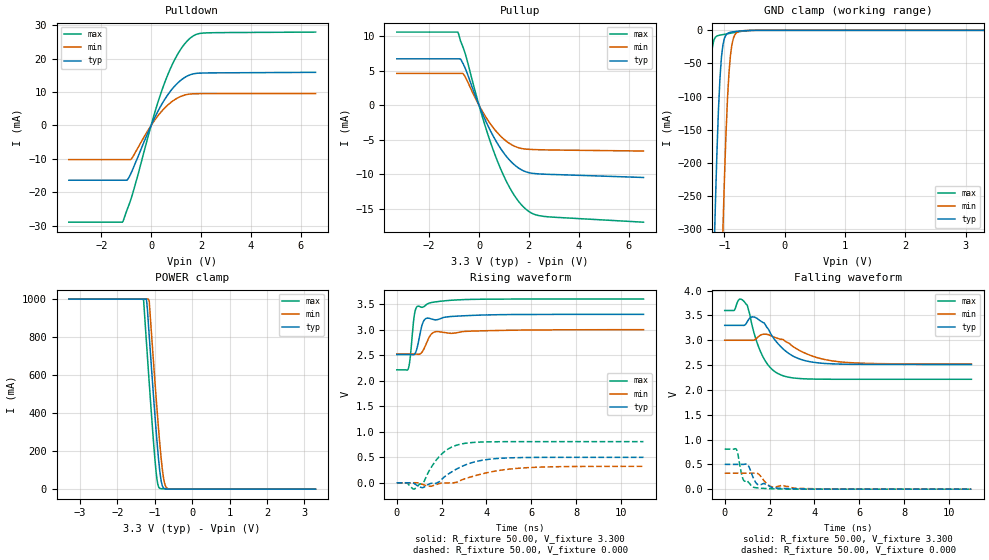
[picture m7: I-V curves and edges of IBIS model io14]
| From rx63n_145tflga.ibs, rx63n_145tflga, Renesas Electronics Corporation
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[Model]   io14
Model_type   I/O
Polarity   Non-Inverting
Enable   Active-High
Vinl  =   0.660V
Vinh  =   2.640V
Vmeas =   1.650V
Cref  =   30.00pF
| variable   typ   min   max
C_comp   4.990pF   4.990pF   4.990pF
| variable   typ   min   max
[Temperature Range]   45.000   105.000   -40.000
| variable   typ   min   max
[Voltage Range]   3.300V   3.000V   3.600V
| variable   typ   min   max
[Pullup Reference]   3.300V   3.000V   3.600V
| variable   typ   min   max
[Pulldown Reference]   0.000V   0.000V   0.000V
| variable   typ   min   max
[POWER Clamp Reference] 3.300V   3.000V   3.600V
| variable   typ   min   max
[GND Clamp Reference]   0.000V   0.000V   0.000V
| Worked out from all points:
|   slope of the pulldown table from 0 to 0.495 V, typ, clamps not added: 68.9 ohm
|   slope of the pullup table from 0 to 0.495 V, typ, clamps not added: 125 ohm
|   GND clamp passes 1 mA (typ) near -0.73 V on its own axis
|   POWER clamp passes 1 mA (typ) near -0.68 V on its own axis
|   rising waveform, R_fixture 50.00, V_fixture 3.300: 20-80 % time 250ps typ, 319ps min, 190ps max; typ from 2.51 V to 3.3 V
|   rising waveform, R_fixture 50.00, V_fixture 0.000: 20-80 % time 1.3ns typ, 1.88ns min, 876ps max; typ from 0 V to 0.499 V
|   falling waveform, R_fixture 50.00, V_fixture 3.300: 20-80 % time 1.06ns typ, 1.44ns min, 744ps max; typ from 3.3 V to 2.51 V
|   falling waveform, R_fixture 50.00, V_fixture 0.000: 20-80 % time 323ps typ, 403ps min, 275ps max; typ from 0.499 V to 0 V
[Pulldown]
| io14 Pulldown rx631_rx63n
| Thu Mar 22 17:15:49 2012
| voltage   I(typ)   I(min)   I(max)
-3.3V     -16.41mA   -10.24mA   -28.98mA
-1.15V    -16.41mA   -10.24mA   -28.98mA
-950mV    -16.26mA   -10.24mA   -24.98mA
-775mV    -13.8mA    -9.865mA   -21.27mA
100mV     1.632mA    1.118mA    2.657mA
525mV     7.544mA    5.064mA    12.43mA
800mV     10.5mA     6.935mA    17.45mA
1.075V    12.77mA    8.279mA    21.46mA
1.6V      15.26mA    9.436mA    26.34mA
1.85V     15.63mA    9.509mA    27.37mA
2.2V      15.73mA    9.534mA    27.72mA
6.6V      15.91mA    9.563mA    27.97mA
[Pullup]
| io14 Pullup rx631_rx63n
| Thu Mar 22 17:15:49 2012
| voltage   I(typ)   I(min)   I(max)
-3.3V     6.712mA    4.602mA    10.58mA
-850mV    6.712mA    4.602mA    10.58mA
-750mV    6.712mA    4.602mA    9.37mA
-600mV    5.722mA    4.375mA    7.966mA
150mV     -1.303mA   -968uA     -1.858mA
700mV     -5.288mA   -3.817mA   -7.715mA
1.025V    -7.054mA   -4.989mA   -10.46mA
1.325V    -8.294mA   -5.739mA   -12.5mA
1.65V     -9.219mA   -6.202mA   -14.18mA
1.95V     -9.695mA   -6.357mA   -15.22mA
2.7V      -9.976mA   -6.451mA   -16.1mA
6.6V      -10.44mA   -6.615mA   -16.9mA
[GND Clamp]
| io14 GNDClamp rx631_rx63n
| Thu Mar 22 17:15:49 2012
| voltage   I(typ)   I(min)   I(max)
-3.3V     -1A        -1A        -1A
-1.325V   -984.4mA   -1A        -342.9mA
-1.225V   -545.7mA   -1A        -51.65mA
-1.175V   -350.6mA   -894.3mA   -14.69mA
-1.15V    -263.5mA   -785.6mA   -10.32mA
-1.125V   -186.6mA   -679.8mA   -8.582mA
-1.075V   -73.83mA   -479.7mA   -7.226mA
-1.025V   -22.04mA   -301.7mA   -6.404mA
-975mV    -7.162mA   -158.6mA   -5.612mA
-925mV    -3.609mA   -64.95mA   -4.78mA
-800mV    -1.61mA    -3.681mA   -2.675mA
3.3V      0A         0A         0A
[POWER Clamp]
| io14 PWRClamp rx631_rx63n
| Thu Mar 22 17:15:49 2012
| voltage   I(typ)   I(min)   I(max)
-3.3V     1A         1A         1A
-1.3V     1A         1A         993.4mA
-1.225V   1A         1A         774.1mA
-1.15V    806.4mA    988.9mA    559mA
-975mV    330.6mA    505.7mA    108.3mA
-925mV    210.2mA    377.1mA    29.71mA
-875mV    107.2mA    256.8mA    5.04mA
-825mV    36.6mA     150.5mA    2.27mA
-775mV    8.07mA     68.23mA    1.837mA
-725mV    2.054mA    21.4mA     1.504mA
-650mV    739uA      2.543mA    864uA
3.3V      0A         0A         0A
[Ramp]
dV/dt_r   0.300/1.31n   0.193/1.88n   0.484/875.62p
dV/dt_f   0.473/1.06n   0.286/1.44n   0.832/744.59p
R_load = 50.00ohm
[Rising Waveform]
| io14 Rising-High rx631_rx63n
| Thu Mar 22 17:15:49 2012
R_fixture = 50.00
V_fixture = 3.300
V_fixture_min = 3.000
V_fixture_max = 3.600
C_fixture = 0.00pF
| Time   V(typ)   V(min)   V(max)
0s        2.512V     2.523V     2.214V
515ps     2.512V     2.523V     2.237V
605ps     2.513V     2.523V     2.48V
775ps     2.513V     2.523V     3.263V
925ps     2.678V     2.519V     3.459V
1.14ns    3.107V     2.569V     3.439V
1.36ns    3.227V     2.773V     3.503V
1.775ns   3.194V     2.962V     3.548V
3.825ns   3.287V     2.978V     3.597V
11ns      3.3V       3V         3.6V
[Rising Waveform]
| io14 Rising-Low rx631_rx63n
| Thu Mar 22 17:15:49 2012
R_fixture = 50.00
V_fixture = 0.000
C_fixture = 0.00pF
| Time   V(typ)   V(min)   V(max)
0s        0V         0V         0V
445ps     0V         0V         -1mV
785ps     -17mV      1mV        -124mV
1.155ns   -96mV      -32mV      -2mV
1.595ns   -7mV       -59mV      343mV
2.05ns    88mV       -5mV       583mV
3.055ns   350mV      82mV       774mV
4.075ns   459mV      202mV      802mV
5.555ns   494mV      289mV      806mV
11ns      499mV      322mV      807mV
[Falling Waveform]
| io14 Falling-High rx631_rx63n
| Thu Mar 22 17:15:49 2012
R_fixture = 50.00
V_fixture = 3.300
V_fixture_min = 3.000
V_fixture_max = 3.600
C_fixture = 0.00pF
| Time   V(typ)   V(min)   V(max)
0s        3.3V       3V         3.6V
420ps     3.3V       3V         3.602V
860ps     3.299V     3V         3.783V
1.005ns   3.373V     3V         3.703V
1.215ns   3.47V      2.999V     3.31V
1.715ns   3.356V     3.12V      2.659V
2.62ns    2.819V     3.009V     2.282V
3.625ns   2.584V     2.732V     2.222V
4.985ns   2.522V     2.573V     2.214V
11ns      2.512V     2.523V     2.214V
[Falling Waveform]
| io14 Falling-Low rx631_rx63n
| Thu Mar 22 17:15:49 2012
R_fixture = 50.00
V_fixture = 0.000
C_fixture = 0.00pF
| Time   V(typ)   V(min)   V(max)
0s        499mV      322mV      807mV
515ps     499mV      322mV      806mV
585ps     499mV      322mV      711mV
760ps     499mV      322mV      290mV
835ps     499mV      322mV      186mV
1.045ns   480mV      322mV      145mV
1.38ns    136mV      327mV      30mV
1.95ns    74mV       81mV       11mV
2.195ns   26mV       43mV       7mV
11ns      0V         0V         0V
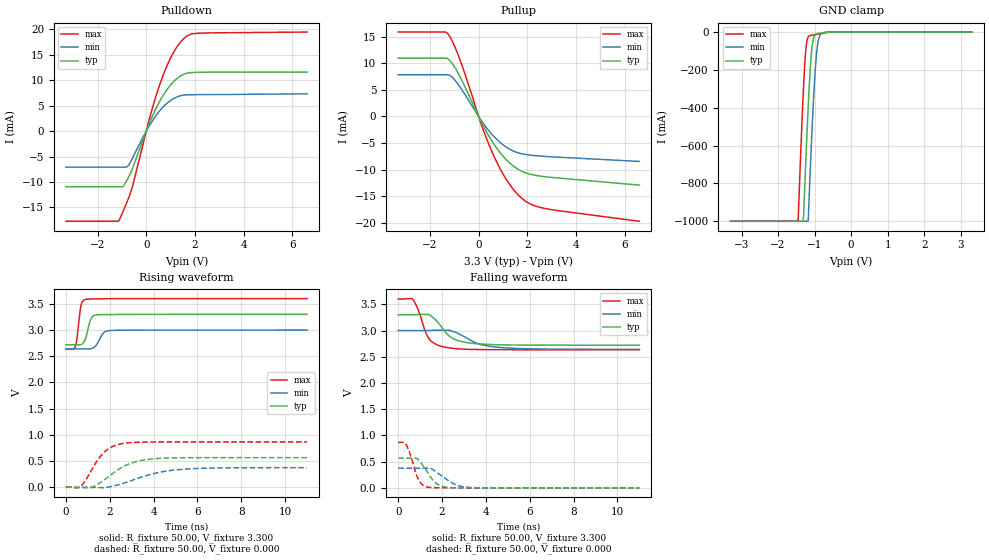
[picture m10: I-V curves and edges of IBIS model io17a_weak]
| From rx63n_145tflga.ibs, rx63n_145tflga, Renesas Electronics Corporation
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[Model]   io17a_weak
Model_type   I/O
Polarity   Non-Inverting
Enable   Active-High
Vinl  =   0.660V
Vinh  =   2.640V
Vmeas =   1.650V
Rref  =   882.000
Cref  =   30.00pF
Vref  =   3.300V
| variable   typ   min   max
C_comp   5.360pF   5.360pF   5.360pF
| variable   typ   min   max
[Temperature Range]   45.000   105.000   -40.000
| variable   typ   min   max
[Voltage Range]   3.300V   3.000V   3.600V
| variable   typ   min   max
[Pullup Reference]   3.300V   3.000V   3.600V
| variable   typ   min   max
[Pulldown Reference]   0.000V   0.000V   0.000V
| variable   typ   min   max
[POWER Clamp Reference] 3.300V   3.000V   3.600V
| variable   typ   min   max
[GND Clamp Reference]   0.000V   0.000V   0.000V
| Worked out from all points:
|   slope of the pulldown table from 0 to 0.495 V, typ, clamps not added: 92.4 ohm
|   slope of the pullup table from 0 to 0.495 V, typ, clamps not added: 117 ohm
|   GND clamp passes 1 mA (typ) near -0.63 V on its own axis
|   rising waveform, R_fixture 50.00, V_fixture 3.300: 20-80 % time 219ps typ, 293ps min, 162ps max; typ from 2.72 V to 3.3 V
|   rising waveform, R_fixture 50.00, V_fixture 0.000: 20-80 % time 1.27ns typ, 1.84ns min, 855ps max; typ from 0 V to 0.566 V
|   falling waveform, R_fixture 50.00, V_fixture 3.300: 20-80 % time 811ps typ, 1.17ns min, 538ps max; typ from 3.3 V to 2.72 V
|   falling waveform, R_fixture 50.00, V_fixture 0.000: 20-80 % time 587ps typ, 802ps min, 404ps max; typ from 0.566 V to 0 V
[Pulldown]
| io17a_weak Pulldown rx631_rx63n
| Thu Mar 22 17:15:49 2012
| voltage   I(typ)   I(min)   I(max)
-3.3V     -10.95mA   -7.081mA   -17.74mA
-1.125V   -10.95mA   -7.081mA   -17.62mA
-950mV    -10.89mA   -7.081mA   -15.74mA
-725mV    -9.054mA   -6.667mA   -13.17mA
-525mV    -6.828mA   -4.938mA   -10.13mA
200mV     2.369mA    1.646mA    3.654mA
650mV     6.684mA    4.539mA    10.45mA
900mV     8.483mA    5.671mA    13.38mA
1.15V     9.86mA     6.473mA    15.72mA
1.625V    11.32mA    7.117mA    18.54mA
2.2V      11.57mA    7.175mA    19.27mA
6.6V      11.61mA    7.333mA    19.49mA
[Pullup]
| io17a_weak Pullup rx631_rx63n
| Thu Mar 22 17:15:49 2012
| voltage   I(typ)   I(min)   I(max)
-3.3V     10.98mA    7.841mA    15.87mA
-1.375V   10.98mA    7.841mA    15.87mA
-1.25V    10.79mA    7.827mA    15.46mA
-1.05V    9.742mA    7.216mA    13.86mA
-800mV    7.799mA    5.799mA    11.09mA
125mV     -1.177mA   -868uA     -1.705mA
650mV     -5.342mA   -3.87mA    -7.66mA
1.25V     -8.636mA   -6.08mA    -12.61mA
1.875V    -10.5mA    -7.104mA   -15.75mA
2.3V      -11.03mA   -7.353mA   -16.78mA
2.9V      -11.41mA   -7.559mA   -17.44mA
6.6V      -12.9mA    -8.451mA   -19.7mA
[GND Clamp]
| io17a_weak GNDClamp rx631_rx63n
| Thu Mar 22 17:15:49 2012
| voltage   I(typ)   I(min)   I(max)
-3.3V     -1A        -1A        -1A
-1.45V    -1A        -1A        -998.8mA
-1.325V   -1A        -1A        -385.7mA
-1.3V     -971.8mA   -1A        -281.5mA
-1.25V    -727.5mA   -1A        -116.3mA
-1.175V   -394.3mA   -998.4mA   -26.12mA
-1.15V    -297.8mA   -877.6mA   -21.18mA
-1.075V   -87.77mA   -537.8mA   -16.82mA
-975mV    -12.79mA   -181.3mA   -13.71mA
-900mV    -7.378mA   -46.43mA   -11.41mA
-825mV    -5.325mA   -9.739mA   -8.598mA
3.3V      0A         0A         0A
[POWER Clamp]
| io17a_weak PWRClamp rx631_rx63n
| Thu Mar 22 17:15:49 2012
| voltage   I(typ)   I(min)   I(max)
-3.3V     0A         0A         0A
0V        0A         0A         0A
3.3V      0A         0A         0A
[Ramp]
dV/dt_r   0.340/1.28n   0.224/1.84n   0.519/854.13p
dV/dt_f   0.348/811.50p  0.216/1.18n   0.580/537.97p
R_load = 50.00ohm
[Rising Waveform]
| io17a_weak Rising-High rx631_rx63n
| Thu Mar 22 17:15:49 2012
R_fixture = 50.00
V_fixture = 3.300
V_fixture_min = 3.000
V_fixture_max = 3.600
C_fixture = 0.00pF
| Time   V(typ)   V(min)   V(max)
0s        2.72V      2.641V     2.634V
425ps     2.72V      2.641V     2.684V
500ps     2.72V      2.641V     2.823V
685ps     2.721V     2.641V     3.455V
920ps     2.869V     2.641V     3.586V
1.16ns    3.228V     2.645V     3.593V
1.4ns     3.289V     2.718V     3.595V
1.72ns    3.295V     2.947V     3.597V
2.035ns   3.296V     2.992V     3.599V
11ns      3.3V       3V         3.6V
[Rising Waveform]
| io17a_weak Rising-Low rx631_rx63n
| Thu Mar 22 17:15:49 2012
R_fixture = 50.00
V_fixture = 0.000
C_fixture = 0.00pF
| Time   V(typ)   V(min)   V(max)
0s        0V         0V         0V
665ps     -3mV       0V         10mV
1.16ns    -2mV       -4mV       318mV
1.655ns   112mV      -8mV       629mV
2.085ns   247mV      16mV       769mV
2.535ns   375mV      65mV       830mV
3.04ns    469mV      136mV      854mV
3.585ns   522mV      213mV      862mV
5.35ns    563mV      344mV      865mV
11ns      566mV      374mV      865mV
[Falling Waveform]
| io17a_weak Falling-High rx631_rx63n
| Thu Mar 22 17:15:49 2012
R_fixture = 50.00
V_fixture = 3.300
V_fixture_min = 3.000
V_fixture_max = 3.600
C_fixture = 0.00pF
| Time   V(typ)   V(min)   V(max)
0s        3.3V       3V         3.6V
650ps     3.3V       3V         3.599V
885ps     3.305V     3V         3.422V
1.375ns   3.307V     3V         2.863V
1.64ns    3.229V     3.005V     2.756V
2.095ns   3.002V     3.005V     2.686V
2.8ns     2.8V       2.931V     2.649V
3.61ns    2.748V     2.754V     2.638V
4.46ns    2.73V      2.685V     2.635V
11ns      2.72V      2.641V     2.634V
[Falling Waveform]
| io17a_weak Falling-Low rx631_rx63n
| Thu Mar 22 17:15:49 2012
R_fixture = 50.00
V_fixture = 0.000
C_fixture = 0.00pF
| Time   V(typ)   V(min)   V(max)
0s        566mV      374mV      865mV
335ps     566mV      374mV      844mV
565ps     566mV      374mV      620mV
915ps     539mV      374mV      164mV
1.34ns    297mV      374mV      14mV
1.615ns   134mV      339mV      4mV
1.935ns   40mV       242mV      2mV
2.545ns   4mV        76mV       0V
3.155ns   1mV        12mV       0V
11ns      0V         0V         0V
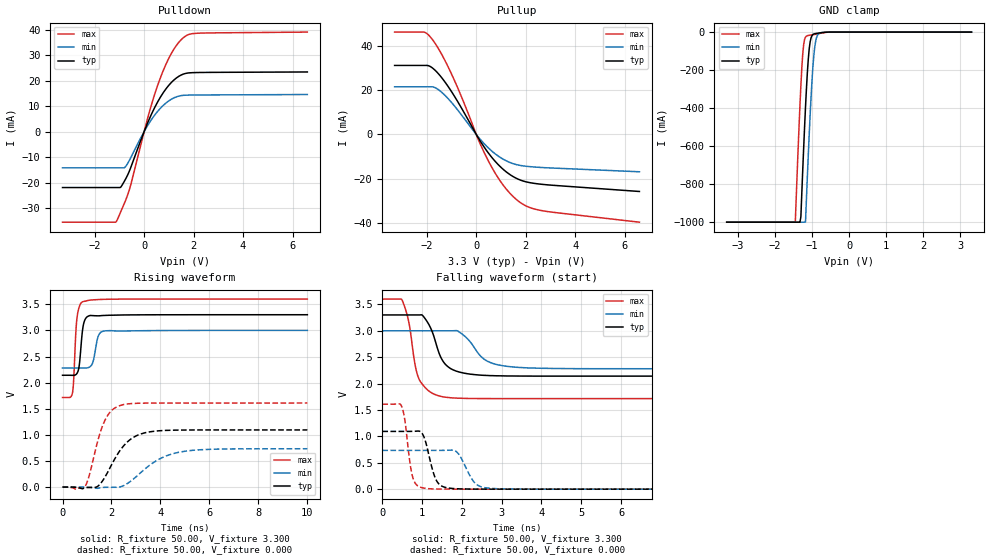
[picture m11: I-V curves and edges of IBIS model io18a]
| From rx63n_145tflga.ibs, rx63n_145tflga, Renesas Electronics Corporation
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[Model]   io18a
Model_type   I/O
Polarity   Non-Inverting
Enable   Active-High
Vinl  =   0.660V
Vinh  =   2.640V
Vmeas =   1.650V
Rref  =   882.000
Cref  =   30.00pF
Vref  =   3.300V
| variable   typ   min   max
C_comp   5.010pF   5.010pF   5.010pF
| variable   typ   min   max
[Temperature Range]   45.000   105.000   -40.000
| variable   typ   min   max
[Voltage Range]   3.300V   3.000V   3.600V
| variable   typ   min   max
[Pullup Reference]   3.300V   3.000V   3.600V
| variable   typ   min   max
[Pulldown Reference]   0.000V   0.000V   0.000V
| variable   typ   min   max
[POWER Clamp Reference] 3.300V   3.000V   3.600V
| variable   typ   min   max
[GND Clamp Reference]   0.000V   0.000V   0.000V
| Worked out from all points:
|   slope of the pulldown table from 0 to 0.495 V, typ, clamps not added: 46.2 ohm
|   slope of the pullup table from 0 to 0.495 V, typ, clamps not added: 58.5 ohm
|   GND clamp passes 1 mA (typ) near -0.63 V on its own axis
|   rising waveform, R_fixture 50.00, V_fixture 3.300: 20-80 % time 144ps typ, 177ps min, 128ps max; typ from 2.14 V to 3.3 V
|   rising waveform, R_fixture 50.00, V_fixture 0.000: 20-80 % time 909ps typ, 1.31ns min, 596ps max; typ from 0 V to 1.09 V
|   falling waveform, R_fixture 50.00, V_fixture 3.300: 20-80 % time 372ps typ, 510ps min, 270ps max; typ from 3.3 V to 2.14 V
|   falling waveform, R_fixture 50.00, V_fixture 0.000: 20-80 % time 231ps typ, 311ps min, 164ps max; typ from 1.09 V to 0 V
[Pulldown]
| io18a Pulldown rx631_rx63n
| Thu Mar 22 17:15:49 2012
| voltage   I(typ)   I(min)   I(max)
-3.3V     -21.93mA   -14.19mA   -35.51mA
-1.125V   -21.93mA   -14.19mA   -35.28mA
-950mV    -21.8mA    -14.19mA   -31.51mA
-725mV    -18.13mA   -13.36mA   -26.35mA
-525mV    -13.67mA   -9.89mA    -20.27mA
200mV     4.744mA    3.297mA    7.31mA
600mV     12.56mA    8.559mA    19.59mA
1.1V      19.27mA    12.7mA     30.64mA
1.375V    21.53mA    13.87mA    34.7mA
1.6V      22.62mA    14.25mA    36.95mA
2.2V      23.2mA     14.39mA    38.62mA
6.6V      23.41mA    14.56mA    39.05mA
[Pullup]
| io18a Pullup rx631_rx63n
| Thu Mar 22 17:15:49 2012
| voltage   I(typ)   I(min)   I(max)
-3.3V     31.12mA    21.48mA    46.18mA
-2.1V     31.12mA    21.48mA    46.13mA
-1.75V    29.8mA     21.42mA    42.5mA
-1.4V     25.65mA    19.04mA    36.2mA
-950mV    18.45mA    13.76mA    26.08mA
100mV     -1.895mA   -1.397mA   -2.764mA
575mV     -9.625mA   -6.998mA   -13.77mA
1.125V    -16.13mA   -11.44mA   -23.43mA
1.7V      -20.25mA   -13.86mA   -30.1mA
2.1V      -21.66mA   -14.51mA   -32.76mA
2.7V      -22.61mA   -15mA      -34.53mA
6.6V      -25.8mA    -16.9mA    -39.66mA
[GND Clamp]
| io18a GNDClamp rx631_rx63n
| Thu Mar 22 17:15:49 2012
| voltage   I(typ)   I(min)   I(max)
-3.3V     -1A        -1A        -1A
-1.45V    -1A        -1A        -998.8mA
-1.325V   -1A        -1A        -385.7mA
-1.3V     -971.8mA   -1A        -281.5mA
-1.25V    -727.5mA   -1A        -116.3mA
-1.175V   -394.3mA   -998.4mA   -26.13mA
-1.15V    -297.8mA   -877.6mA   -21.18mA
-1.075V   -87.77mA   -537.8mA   -16.82mA
-975mV    -12.8mA    -181.3mA   -13.72mA
-900mV    -7.379mA   -46.43mA   -11.41mA
-825mV    -5.325mA   -9.739mA   -8.6mA
3.3V      0A         0A         0A
[POWER Clamp]
| io18a PWRClamp rx631_rx63n
| Thu Mar 22 17:15:49 2012
| voltage   I(typ)   I(min)   I(max)
-3.3V     0A         0A         0A
0V        0A         0A         0A
3.3V      0A         0A         0A
[Ramp]
dV/dt_r   0.657/908.19p  0.440/1.31n   0.966/594.87p
dV/dt_f   0.696/371.63p  0.432/508.51p  1.131/269.91p
R_load = 50.00ohm
[Rising Waveform]
| io18a Rising-High rx631_rx63n
| Thu Mar 22 17:15:49 2012
R_fixture = 50.00
V_fixture = 3.300
V_fixture_min = 3.000
V_fixture_max = 3.600
C_fixture = 0.00pF
| Time   V(typ)   V(min)   V(max)
0s        2.141V     2.28V      1.715V
405ps     2.14V      2.28V      1.8V
450ps     2.139V     2.28V      2.011V
590ps     2.176V     2.28V      3.232V
685ps     2.336V     2.28V      3.453V
845ps     3.088V     2.28V      3.552V
1.2ns     3.285V     2.347V     3.583V
1.445ns   3.279V     2.869V     3.59V
1.69ns    3.286V     2.987V     3.595V
10ns      3.3V       3V         3.6V
[Rising Waveform]
| io18a Rising-Low rx631_rx63n
| Thu Mar 22 17:15:49 2012
R_fixture = 50.00
V_fixture = 0.000
C_fixture = 0.00pF
| Time   V(typ)   V(min)   V(max)
0s        0V         0V         0V
915ps     -16mV      0V         10mV
1.09ns    -7mV       -5mV       220mV
1.4ns     4mV        -23mV      813mV
1.675ns   147mV      -6mV       1.218V
1.94ns    370mV      -4mV       1.433V
2.305ns   671mV      -1mV       1.554V
3.205ns   1.018V     281mV      1.606V
4.72ns    1.091V     663mV      1.609V
10ns      1.094V     734mV      1.61V
[Falling Waveform]
| io18a Falling-High rx631_rx63n
| Thu Mar 22 17:15:49 2012
R_fixture = 50.00
V_fixture = 3.300
V_fixture_min = 3.000
V_fixture_max = 3.600
C_fixture = 0.00pF
| Time   V(typ)   V(min)   V(max)
0s        3.3V       3V         3.6V
490ps     3.3V       3V         3.589V
650ps     3.3V       3V         3.216V
910ps     3.3V       3V         2.106V
1.17ns    3.118V     3V         1.859V
1.47ns    2.497V     3V         1.758V
1.935ns   2.218V     2.976V     1.723V
2.555ns   2.156V     2.464V     1.716V
3.14ns    2.144V     2.326V     1.715V
10ns      2.141V     2.28V      1.715V
[Falling Waveform]
| io18a Falling-Low rx631_rx63n
| Thu Mar 22 17:15:49 2012
R_fixture = 50.00
V_fixture = 0.000
C_fixture = 0.00pF
| Time   V(typ)   V(min)   V(max)
0s        1.094V     734mV      1.61V
480ps     1.094V     734mV      1.577V
560ps     1.094V     734mV      1.333V
755ps     1.095V     734mV      250mV
1.005ns   1.05V      734mV      26mV
1.34ns    194mV      734mV      3mV
1.67ns    21mV       738mV      1mV
1.895ns   7mV        685mV      0V
2.585ns   1mV        27mV       0V
10ns      0V         0V         0V
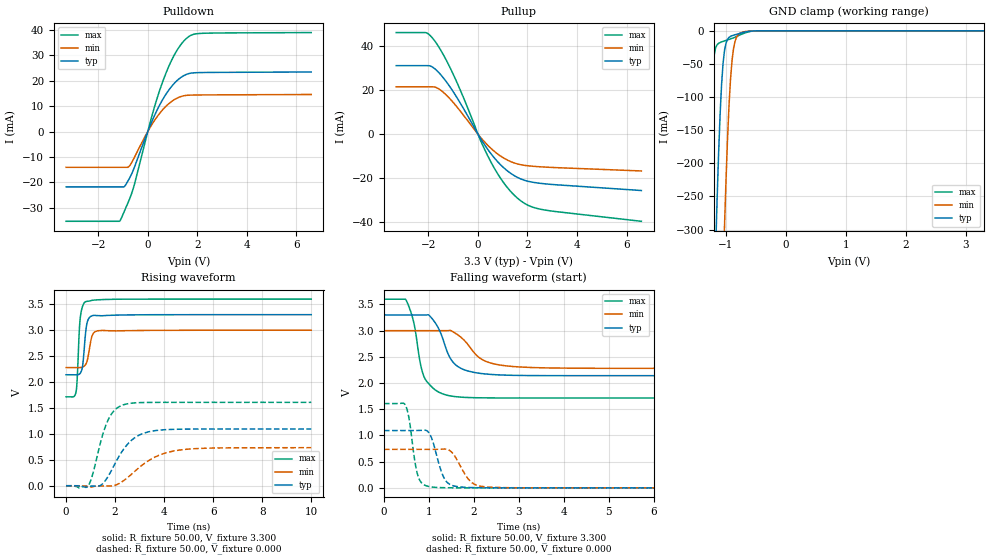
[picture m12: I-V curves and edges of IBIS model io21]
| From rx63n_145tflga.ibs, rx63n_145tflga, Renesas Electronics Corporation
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[Model]   io21
Model_type   I/O
Polarity   Non-Inverting
Enable   Active-High
Vinl  =   0.660V
Vinh  =   2.640V
Vmeas =   1.650V
Cref  =   30.00pF
| variable   typ   min   max
C_comp   4.380pF   4.380pF   4.380pF
| variable   typ   min   max
[Temperature Range]   45.000   105.000   -40.000
| variable   typ   min   max
[Voltage Range]   3.300V   3.000V   3.600V
| variable   typ   min   max
[Pullup Reference]   3.300V   3.000V   3.600V
| variable   typ   min   max
[Pulldown Reference]   0.000V   0.000V   0.000V
| variable   typ   min   max
[POWER Clamp Reference] 3.300V   3.000V   3.600V
| variable   typ   min   max
[GND Clamp Reference]   0.000V   0.000V   0.000V
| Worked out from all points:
|   slope of the pulldown table from 0 to 0.495 V, typ, clamps not added: 46.2 ohm
|   slope of the pullup table from 0 to 0.495 V, typ, clamps not added: 58.5 ohm
|   GND clamp passes 1 mA (typ) near -0.63 V on its own axis
|   rising waveform, R_fixture 50.00, V_fixture 3.300: 20-80 % time 137ps typ, 171ps min, 118ps max; typ from 2.14 V to 3.3 V
|   rising waveform, R_fixture 50.00, V_fixture 0.000: 20-80 % time 906ps typ, 1.3ns min, 591ps max; typ from 0 V to 1.09 V
|   falling waveform, R_fixture 50.00, V_fixture 3.300: 20-80 % time 365ps typ, 506ps min, 264ps max; typ from 3.3 V to 2.14 V
|   falling waveform, R_fixture 50.00, V_fixture 0.000: 20-80 % time 229ps typ, 310ps min, 163ps max; typ from 1.09 V to 0 V
[Pulldown]
| io21 Pulldown rx631_rx63n
| Thu Mar 22 17:15:49 2012
| voltage   I(typ)   I(min)   I(max)
-3.3V     -21.77mA   -14.07mA   -35.31mA
-1.125V   -21.77mA   -14.07mA   -35.14mA
-950mV    -21.7mA    -14.07mA   -31.41mA
-725mV    -18.09mA   -13.33mA   -26.26mA
-525mV    -13.65mA   -9.879mA   -20.22mA
200mV     4.739mA    3.295mA    7.297mA
650mV     13.38mA    9.09mA     20.88mA
900mV     16.98mA    11.36mA    26.76mA
1.15V     19.75mA    12.97mA    31.46mA
1.625V    22.69mA    14.27mA    37.13mA
2.2V      23.2mA     14.39mA    38.62mA
6.6V      23.41mA    14.56mA    38.92mA
[Pullup]
| io21 Pullup rx631_rx63n
| Thu Mar 22 17:15:49 2012
| voltage   I(typ)   I(min)   I(max)
-3.3V     31.12mA    21.48mA    46.18mA
-2.1V     31.12mA    21.48mA    46.12mA
-1.75V    29.78mA    21.41mA    42.47mA
-1.375V   25.28mA    18.78mA    35.66mA
-950mV    18.43mA    13.76mA    26.05mA
100mV     -1.894mA   -1.396mA   -2.761mA
550mV     -9.261mA   -6.742mA   -13.23mA
1.1V      -15.88mA   -11.28mA   -23.05mA
1.7V      -20.25mA   -13.85mA   -30.09mA
2.1V      -21.66mA   -14.5mA    -32.75mA
2.7V      -22.61mA   -15mA      -34.53mA
6.6V      -25.66mA   -16.76mA   -39.66mA
[GND Clamp]
| io21 GNDClamp rx631_rx63n
| Thu Mar 22 17:15:49 2012
| voltage   I(typ)   I(min)   I(max)
-3.3V     -1A        -1A        -1A
-1.325V   -892.4mA   -1A        -322.7mA
-1.25V    -599.4mA   -1A        -104.7mA
-1.175V   -333.9mA   -818.1mA   -25.78mA
-1.15V    -256.1mA   -722.4mA   -21.07mA
-1.075V   -81.26mA   -452mA     -16.8mA
-1.025V   -29.14mA   -292.9mA   -15.21mA
-975mV    -12.7mA    -162mA     -13.7mA
-925mV    -8.324mA   -72.18mA   -12.19mA
-850mV    -5.983mA   -15.83mA   -9.588mA
-700mV    -2.191mA   -1.49mA    -3.729mA
3.3V      0A         0A         0A
[POWER Clamp]
| io21 PWRClamp rx631_rx63n
| Thu Mar 22 17:15:49 2012
| voltage   I(typ)   I(min)   I(max)
-3.3V     0A         0A         0A
0V        0A         0A         0A
3.3V      0A         0A         0A
[Ramp]
dV/dt_r   0.656/905.40p  0.440/1.31n   0.966/591.33p
dV/dt_f   0.696/365.45p  0.432/503.21p  1.131/263.54p
R_load = 50.00ohm
[Rising Waveform]
| io21 Rising-High rx631_rx63n
| Thu Mar 22 17:15:49 2012
R_fixture = 50.00
V_fixture = 3.300
V_fixture_min = 3.000
V_fixture_max = 3.600
C_fixture = 0.00pF
| Time   V(typ)   V(min)   V(max)
0s        2.141V     2.28V      1.715V
405ps     2.14V      2.28V      1.807V
450ps     2.139V     2.28V      2.035V
535ps     2.151V     2.279V     2.96V
575ps     2.169V     2.28V      3.224V
680ps     2.333V     2.291V     3.47V
800ps     2.97V      2.342V     3.551V
1.055ns   3.278V     2.883V     3.576V
1.295ns   3.282V     2.989V     3.587V
10ns      3.3V       3V         3.6V
[Rising Waveform]
| io21 Rising-Low rx631_rx63n
| Thu Mar 22 17:15:49 2012
R_fixture = 50.00
V_fixture = 0.000
C_fixture = 0.00pF
| Time   V(typ)   V(min)   V(max)
0s        0V         0V         0V
910ps     -16mV      -15mV      9mV
1.085ns   -7mV       -20mV      221mV
1.395ns   4mV        -4mV       817mV
1.665ns   144mV      -4mV       1.217V
1.93ns    367mV      1mV        1.433V
2.295ns   670mV      81mV       1.554V
3.035ns   988mV      372mV      1.604V
4.38ns    1.088V     669mV      1.609V
10ns      1.094V     734mV      1.609V
[Falling Waveform]
| io21 Falling-High rx631_rx63n
| Thu Mar 22 17:15:49 2012
R_fixture = 50.00
V_fixture = 3.300
V_fixture_min = 3.000
V_fixture_max = 3.600
C_fixture = 0.00pF
| Time   V(typ)   V(min)   V(max)
0s        3.3V       3V         3.6V
485ps     3.3V       3V         3.593V
650ps     3.3V       3V         3.204V
805ps     3.3V       3V         2.397V
900ps     3.3V       3V         2.106V
1.17ns    3.112V     3V         1.852V
1.445ns   2.524V     3.003V     1.76V
2.2ns     2.179V     2.442V     1.718V
2.855ns   2.148V     2.317V     1.716V
10ns      2.141V     2.28V      1.715V
[Falling Waveform]
| io21 Falling-Low rx631_rx63n
| Thu Mar 22 17:15:49 2012
R_fixture = 50.00
V_fixture = 0.000
C_fixture = 0.00pF
| Time   V(typ)   V(min)   V(max)
0s        1.094V     734mV      1.609V
475ps     1.094V     734mV      1.581V
555ps     1.094V     734mV      1.34V
750ps     1.095V     734mV      249mV
1.015ns   1.033V     734mV      23mV
1.335ns   192mV      740mV      3mV
1.635ns   24mV       520mV      1mV
1.945ns   6mV        108mV      0V
2.32ns    1mV        15mV       0V
10ns      0V         0V         0V
